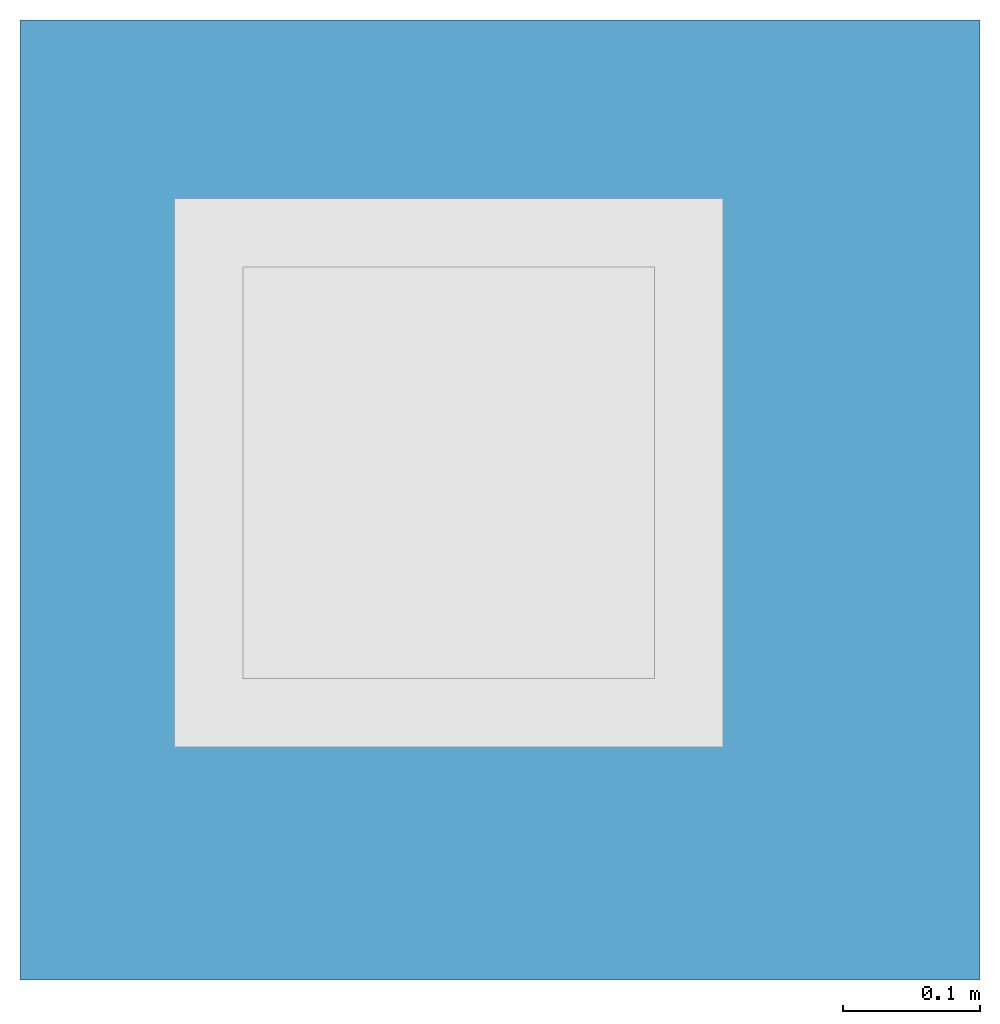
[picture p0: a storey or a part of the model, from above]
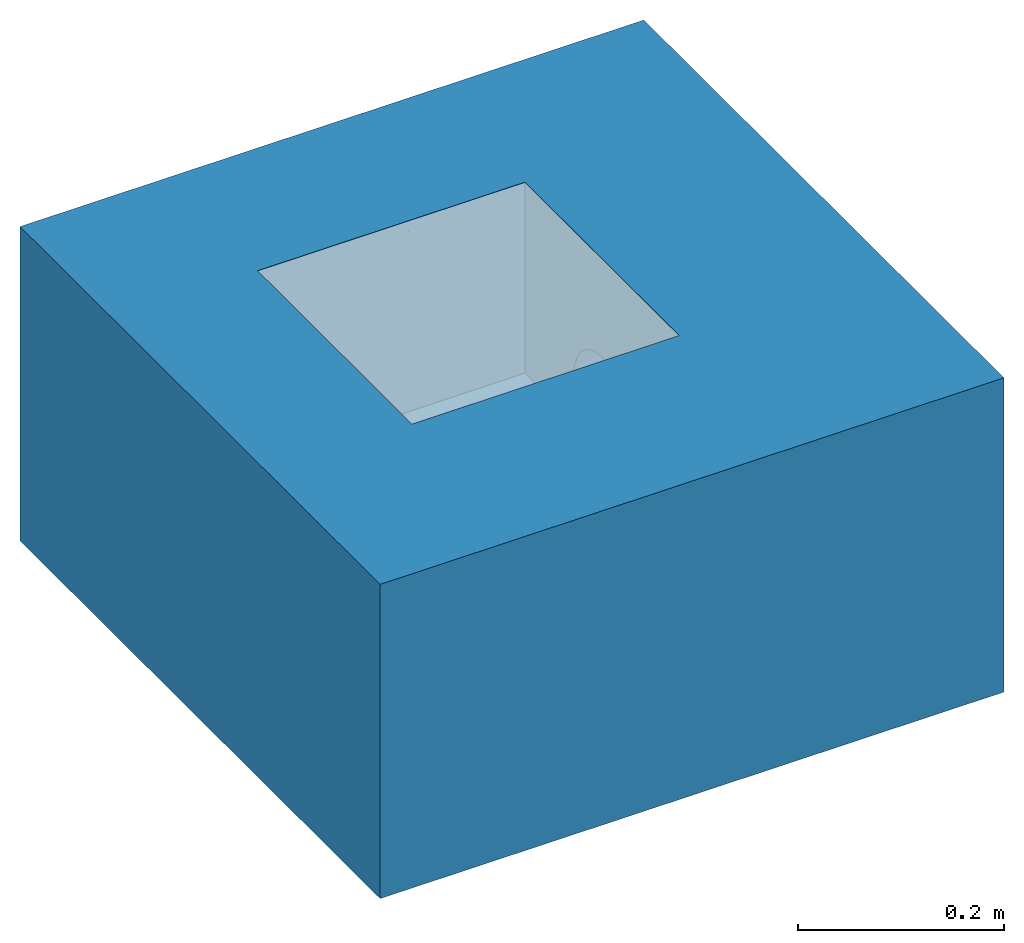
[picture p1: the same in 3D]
Properties of the parts of a building model (IFC2X3)

# File
Description: ViewDefinition [CoordinationView]
File name: Project Number
Time: 2014-10-13T17:45:41
Written by: The EXPRESS Data Manager Version 5.01.0100.02.64mod : 6 Jun 2012
Made in: 20130308_1515(x64) - Exporter 2014.0.2013.0308 - Default UI
Comment: STEP Physical File produced by: The EXPRESS Data Manager Version 5.01.0100.02.64mod : 6 Jun 2012 * Module: EDMstepFileFactory/EDMstandAlone * Creation date: Mon Oct 13 17:45:41 2014 * Host: IN-BLR-PC-0012 * Database: C:\Users\pponnur\AppData\Local\Temp\{D5CA7D8D-9077-4933-ABD1-2CF2366D853F}\ifc * Database version: 5507 * Database creation date: Mon Oct 13 17:45:40 2014 * Schema: IFC2X3 * Model: DataRepository.ifc * Model creation date: Mon Oct 13 17:45:40 2014 * Header model: DataRepository.ifc_HeaderModel * Header model creation date: Mon Oct 13 17:45:40 2014 * EDMuser: sdai-user * EDMgroup: sdai-group * License ID and type: 5605 : Permanent license. Expiry date: * EDMstepFileFactory options: 020000

# IfcProject, Project Number
LongName: Project Name; Phase: Project Status

# IfcSite, Default
RefLatitude: 42, 21, 30, 344238; RefLongitude: -71, -3, -35, -194702; RefElevation: 0 mm

# IfcBuilding
Pset_BuildingCommon - NumberOfStoreys: 1
Other - Project Name: Project Name; Client Name: Owner; Project Number: Project Number; Project Status: Project Status; Project Issue Date: Issue Date; Project Address: Enter address here

# IfcBuildingStorey, Level 1
LongName: Level 1; Elevation: 0 mm
Constraints - Elevation Base: Project Base Point; Elevation: 0 mm
Graphics - Symbol at End 2 Default: yes; Symbol at End 1 Default: no; Symbol: Level Head - Circle: Level Head - Circle; Line Weight: 1; Color: 0; Line Pattern: Grid Line 1/2"
Identity Data - Building Story: yes; Structural: no; Name: Level 1
Dimensions - Computation Height: 0 mm

# IfcFlowTerminal: 408085 Body / 408243 Top, ACO BD Gully 218 Telescopic - Thin Bed - Horizontal Outlet with Location Flange - 300x300:408085 Body / 408243 Top:192989
In: Level 1
Material: Stainless Steel AISI 304, Rubber, Nitrile
Other - Thin Bed Void: no; 408209 - Raising Piece with Location Flange: no; Raising Piece Detail: no
Mechanical - System Classification: Sanitary
Construction - 408036 - 268 x 268mm - Quadrato Grating - Brushed - Stainless steel 304: no; 408220 - Foul Air Trap & 408221 - Foul Air Trap Support Ring: yes; 408040 - 268 x 268mm - HeelSafe Grating - Brushed - Stainless Steel 304: no; 408037 - 268 x 268mm - Ladder Grating - Slip Resistant - Stainless steel 304: no; 408034 - 268 x 268mm - Mesh Grating - Slip Resistant - Stainless Steel 304: no; 408038 - 268 x 268mm - Ladder Grating - Plain - Stainless Steel 304: no; 408035 - 268 x 268mm - Mesh Grating - Plain - Stainless Steel 304: no; 408223 - Silt Basket: yes; 408041 - 268 x 268mm - Arla Grating - Slip Resistant - Stainless Steel 304: no; 408042 - 268 x 268mm - Volcano Grating - Slip Resistant - Stainless Steel 304: no; 408045 - 268 x 268mm - Ladder Grating - Plain - Stainless Steel 304: no; 408039 - 268 x 268mm - Slot Cover - Plain - Stainless Steel 304: no
Identity Data - Mark: 4; Website: www.acobd.com; Manufacturer: ACO Building Drainage; Watermarked By: www.acobd.com; Water Marked With: BIM Manager Premium Suite; Water Mark 2: This file is water marked and users are prohibited to reproduce, adapt, distribute this information; E-mail Sales: abdcommercial@aco.co.uk; Water Mark 1: This file is the property of ACO Technologies PLC; Telephone: +44 (0)1462 816666; E-mail Technical: abdtechnical@aco.co.uk; Fax: +44 (0)1462 851490; Address: ACO Business Centre, Caxton Road, Bedford, MK41 0LF
Dimensions - Floor Void End: -226.5 mm; FFL To Gully Top Height: 68 mm; Rasing Piece Height: 500 mm; Floor To Gully Height: 73.5 mm; Thin Bed Void Start: 0 mm; Thin Bed Void End: 2 mm
Constraints - Level: Level: Level 1
Phasing - Phase Created: New Construction
Model Properties - Raising Piece Product Code 408209: NA; Grating Product Code 408041: Load Class L15 (EN 1253) - Arla Grating - Slip Resistant - Stainless steel 1.4301 (EN 10088) - 268 x 268 x 30mm; Grating Product Code 408037: Load Class M125 (EN 1253) - Ladder Grating - Slip Resistant - Stainless steel 1.4301 (EN 10088) - 268 x 268 x 30mm; Grating Product Code 408045: Load Class C250 (EN 1253) - Ladder Grating - Plain - Stainless steel 1.4301 (EN 10088) - 268 x 268 x 30mm; Grating Product Code 408040: Load Class L15 (EN 1253) - Heelsafe Grating - Brushed - Stainless steel 1.4301 (EN 10088) - 268 x 268 x 30mm; Product Code 408225: Friction Ring Installation Set - Nitrile; Product Code 408220: Foul Air Trap - Stainless Steel 304; Product Code 408223: Silt Basket - Stainless Steel 304; Grating Product Code 408034: Load Class L15 (EN 1253) - Mesh Grating - Slip Resistant - Stainless steel 1.4301 (EN 10088) - 268 x 268 x 30mm; Product Code 408221: Foul Air Trap Support Ring - Nitrile; Grating Product Code 408035: Load Class L15 (EN 1253) - Mesh Grating - Plain - Stainless steel 1.4301 (EN 10088) - 268 x 268 x 30mm; Grating Product Code 408042: Load Class M125 (EN 1253) - Volcano Grating - Slip Resistant - Stainless steel 1.4301 (EN 10088) - 268 x 268 x 30mm; Grating Product Code 408036: Load Class M125 (EN 1253) - Ladder Grating - Slip Resistant - Stainless steel 1.4301 (EN 10088) - 268 x 268 x 30mm; Grating Product Code 408039: Load Class M125 (EN 1253) - Slot Cover - Plain - Stainless steel 1.4301 (EN 10088) - 268 x 268 x 30mm; Grating Product Code 408038: Load Class M125 (EN 1253) - Ladder Grating -Plain - Stainless steel 1.4301 (EN 10088) - 268 x 268 x 30mm
Pset_ManufacturerTypeInformation - Manufacturer: ACO Building Drainage
General - Outlet Diameter (mm): 110; NBS Specification: R11 ABOVE GROUND FOUL DRAINAGE SYSTEMS : Clause 315; Gully Product Code: 408085; Gully Top Product Code: 408243; Load Class: A15 - C250 (EN 1253); Foul Air Trap Seal Material: NBR; Product Range: ACO Gully 218; Foul Air Trap Seal Colour: Black; Gully Material: Stainless Steel Grade 304 (EN 1253); Maintenance guidelines: http://issuu.com/acobuildingdrainage/docs/120820112708-138bdc871b784edfa2b6b8197acfd881?e=0; Gully top Grate size (mm): 300 x 300; Product Type: Point drainage; Product Standard: EN 1253; Gully Recycled Material Content: 20 - 30 %; Gully Top Size (mm): 242mm Diameter; Gully Flange Type: Location; Foul Air Trap Seal Recyclable: Fully recyclable; Foul Air Trap Seal Recycled Material Content: 0%; Gully Recyclable: Fully recyclable; Price: POA - contact ACO; Gully Product Description: ACO Gully 218 Telescopic Flange Type DN110 Horizontal with Foul Air Trap; Gully Top Product Description: ACO Gully 218 Telescopic Top for Thin Bed top or Tanked Flooring; Gully Colour: passivated stainless steel surface ( matt grey); Installation guidelines: http://issuu.com/acobuildingdrainage/docs/120820112708-138bdc871b784edfa2b6b8197acfd881?e=0; Flow Rate (l/s): 4.4 - 5.5 l/s
Materials and Finishes - Material: Stainless Steel AISI 304

# IfcOpeningElement: Recess
In: Level 1
Phasing - Phase Created: New Construction
Dimensions - Perimeter: 2800 mm; Volume: 5.71492 ft3; Thickness: 372.8 mm; Area: 5.27432 ft2
Constraints - Room Bounding: yes; Related to Mass: no; Level: Level: Level 1; Height Offset From Level: 0 mm
Structural - Structural: no; Enable Analytical Model: no
Analytical Properties - Roughness: 3; Absorptance: 0.7; Heat Transfer Coefficient (U): 1.55882; Thermal Resistance (R): 0.641509; Thermal mass: 53301.1
Identity Data - Assembly Description: Floor Construction; Assembly Code: B1010
Construction - Function: Interior; Default Thickness: 372.8 mm
Graphics - Coarse Scale Fill Color: 0

# IfcSlab: Floor:Generic - 12", Floor:Generic - 12":184145
In: Level 1
PredefinedType: FLOOR; Material: Plywood, Sheathing 68 mm, Default Floor 304.8 mm
Phasing - Phase Created: New Construction
Dimensions - Perimeter: 2800 mm; Volume: 5.71492 ft3; Thickness: 372.8 mm; Area: 5.27432 ft2
Constraints - Room Bounding: yes; Related to Mass: no; Level: Level: Level 1; Height Offset From Level: 0 mm
Structural - Structural: no; Enable Analytical Model: no
Pset_SlabCommon - Reference: Generic - 12"; IsExternal: no; LoadBearing: yes; ThermalTransmittance: 1.55882 kg/K/s3
Analytical Properties - Roughness: 3; Absorptance: 0.7; Heat Transfer Coefficient (U): 1.55882; Thermal Resistance (R): 0.641509; Thermal mass: 53301.1
Identity Data - Assembly Description: Floor Construction; Assembly Code: B1010
Construction - Function: Interior; Default Thickness: 372.8 mm
Graphics - Coarse Scale Fill Color: 0
